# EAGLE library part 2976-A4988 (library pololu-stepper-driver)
A4988 Stepper Motor Driver Carrier; Black Edition (Bulk; No Header Pins) #2976 A4988 Stepper Motor Driver Carrier; Black Edition (Bulk; No Header Pins) in Japan, Suzaku Lab. Ltd. #2976 A4988 ステッピングモータドライバボード Black Edition (バルク品 ピンヘッダ無し)

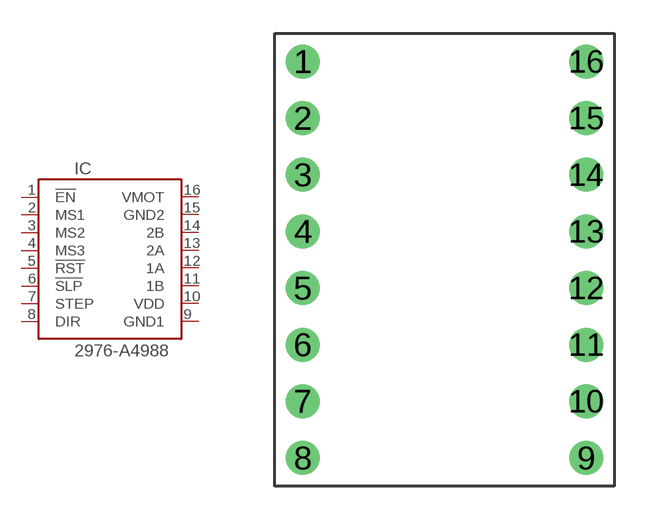
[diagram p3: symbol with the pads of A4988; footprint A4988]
Designator prefix IC

## 2976-A4988  [A4988]
1  !EN  pas
2  MS1  pas
3  MS2  pas
4  MS3  pas
5  !RST  pas
6  !SLP  pas
7  STEP  in
8  DIR  in
9  GND1  pwr
10  VDD  pwr
11  1B  out
12  1A  out
13  2A  out
14  2B  out
15  GND2  pwr
16  VMOT  pwr

## Footprint A4988 (pad centres in mm)
A4988 Stepper Motor Driver Carriers
drill 1.016: 1 -6.35,8.89; 2 -6.35,6.35; 3 -6.35,3.81; 4 -6.35,1.27; 5 -6.35,-1.27; 6 -6.35,-3.81; 7 -6.35,-6.35; 8 -6.35,-8.89; 9 6.35,-8.89; 10 6.35,-6.35; 11 6.35,-3.81; 12 6.35,-1.27; 13 6.35,1.27; 14 6.35,3.81; 15 6.35,6.35; 16 6.35,8.89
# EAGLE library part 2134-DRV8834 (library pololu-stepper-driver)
DRV8834 Low-Voltage Stepper Motor Driver Carrier #2134 DRV8834 Low-Voltage Stepper Motor Driver Carrier in Japan, Suzaku Lab. Ltd. #2134 DRV8834 低電圧用ステッピングモータドライバ

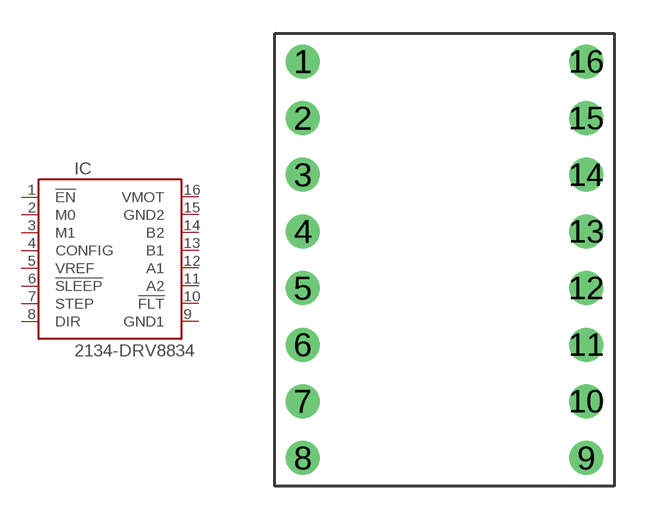
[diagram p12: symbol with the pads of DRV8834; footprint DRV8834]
Designator prefix IC

## 2134-DRV8834  [DRV8834]
1  !EN  pas
2  M0  pas
3  M1  pas
4  CONFIG  pas
5  VREF  pas
6  !SLEEP  in
7  STEP  in
8  DIR  in
9  GND1  pwr
10  !FLT  oc
11  A2  out
12  A1  out
13  B1  out
14  B2  out
15  GND2  pwr
16  VMOT  pwr

## Footprint DRV8834 (pad centres in mm)
DRV8834 Low-Voltage Stepper Motor Driver
drill 1.016: 1 -6.35,8.89; 2 -6.35,6.35; 3 -6.35,3.81; 4 -6.35,1.27; 5 -6.35,-1.27; 6 -6.35,-3.81; 7 -6.35,-6.35; 8 -6.35,-8.89; 9 6.35,-8.89; 10 6.35,-6.35; 11 6.35,-3.81; 12 6.35,-1.27; 13 6.35,1.27; 14 6.35,3.81; 15 6.35,6.35; 16 6.35,8.89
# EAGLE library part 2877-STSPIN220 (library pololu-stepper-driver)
STSPIN220 Low-Voltage Stepper Motor Driver Carrier (Header Pins Soldered) #2877 STSPIN220 Low-Voltage Stepper Motor Driver Carrier (Header Pins Soldered) in Japan, Suzaku Lab. Ltd. #2877 STSPIN220ステッピングモータードライバボード（ハンダ付済み）

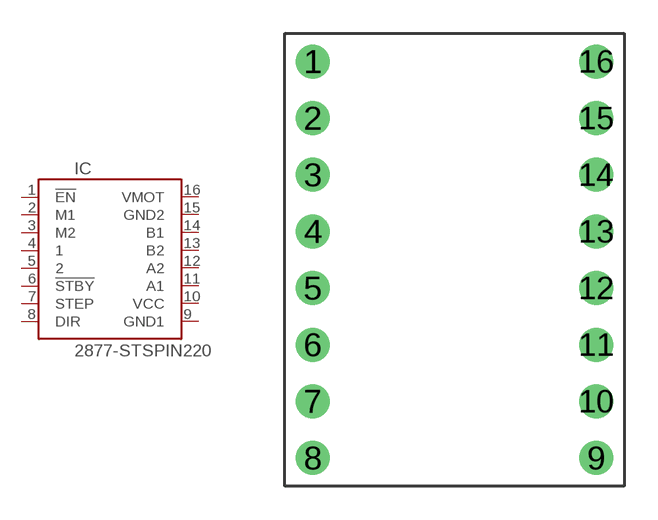
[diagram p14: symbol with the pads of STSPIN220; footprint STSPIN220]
Designator prefix IC

## 2877-STSPIN220  [STSPIN220]
1  !EN  pas
2  M1  in
3  M2  in
4  1  pas
5  2  pas
6  !STBY  pas
7  STEP  in
8  DIR  in
9  GND1  pwr
10  VCC  pwr
11  A1  out
12  A2  out
13  B2  out
14  B1  out
15  GND2  pwr
16  VMOT  pwr

## Footprint STSPIN220 (pad centres in mm)
STSPIN220 Low-Voltage Stepper Motor Driver
drill 1.016: 1 -6.35,8.89; 2 -6.35,6.35; 3 -6.35,3.81; 4 -6.35,1.27; 5 -6.35,-1.27; 6 -6.35,-3.81; 7 -6.35,-6.35; 8 -6.35,-8.89; 9 6.35,-8.89; 10 6.35,-6.35; 11 6.35,-3.81; 12 6.35,-1.27; 13 6.35,1.27; 14 6.35,3.81; 15 6.35,6.35; 16 6.35,8.89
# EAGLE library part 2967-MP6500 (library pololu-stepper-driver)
MP6500 Stepper Motor Driver Carrier; Potentiometer Current Control (Header Pins Soldered) #2967 MP6500 Stepper Motor Driver Carrier; Potentiometer Current Control (Header Pins Soldered) in Japan, Suzaku Lab. Ltd. #2967 MP6500ステッピングモータドライバボード ポテンショメータ式電流制御 (ヘッダーピン実装済み)

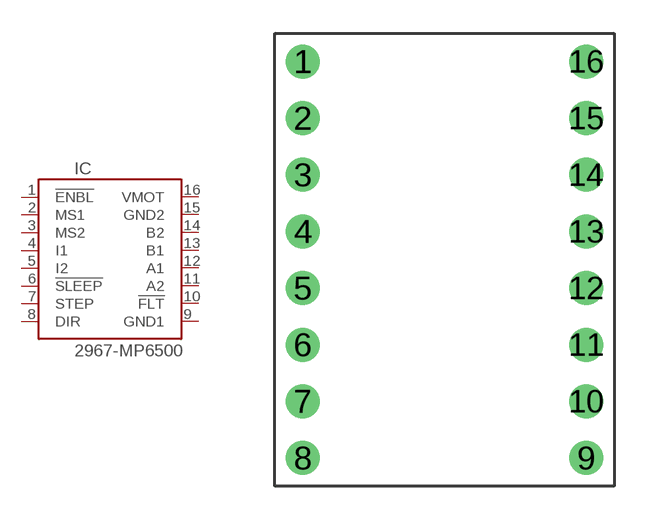
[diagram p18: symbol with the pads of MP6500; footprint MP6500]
Designator prefix IC

## 2967-MP6500  [MP6500]
1  !ENBL  pas
2  MS1  pas
3  MS2  pas
4  I1  pas
5  I2  pas
6  !SLEEP  in
7  STEP  in
8  DIR  in
9  GND1  pwr
10  !FLT  oc
11  A2  out
12  A1  out
13  B1  out
14  B2  out
15  GND2  pwr
16  VMOT  pwr

## Footprint MP6500 (pad centres in mm)
MP6500 Stepper Motor Driver
drill 1.016: 1 -6.35,8.89; 2 -6.35,6.35; 3 -6.35,3.81; 4 -6.35,1.27; 5 -6.35,-1.27; 6 -6.35,-3.81; 7 -6.35,-6.35; 8 -6.35,-8.89; 9 6.35,-8.89; 10 6.35,-6.35; 11 6.35,-3.81; 12 6.35,-1.27; 13 6.35,1.27; 14 6.35,3.81; 15 6.35,6.35; 16 6.35,8.89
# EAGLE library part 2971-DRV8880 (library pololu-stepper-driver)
DRV8880 Stepper Motor Driver Carrier #2971 DRV8880 Stepper Motor Driver Carrier in Japan, Suzaku Lab. Ltd. #2971 DRV8880ステッピングモータドライバボード

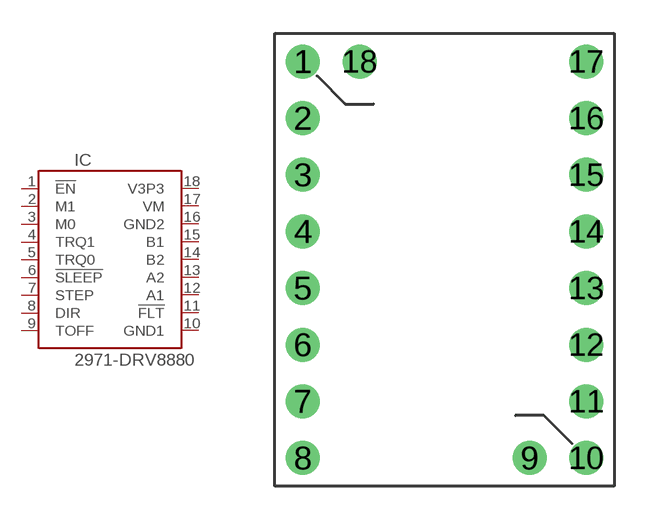
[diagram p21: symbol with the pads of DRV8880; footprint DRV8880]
Designator prefix IC

## 2971-DRV8880  [DRV8880]
1  !EN  pas
2  M1  pas
3  M0  pas
4  TRQ1  pas
5  TRQ0  pas
6  !SLEEP  in
7  STEP  in
8  DIR  in
9  TOFF  pas
10  GND1  pwr
11  !FLT  oc
12  A1  out
13  A2  out
14  B2  out
15  B1  out
16  GND2  pwr
17  VM  pwr
18  V3P3  sup

## Footprint DRV8880 (pad centres in mm)
DRV8880 Stepper Motor Driver
drill 1.016: 1 -6.35,8.89; 2 -6.35,6.35; 3 -6.35,3.81; 4 -6.35,1.27; 5 -6.35,-1.27; 6 -6.35,-3.81; 7 -6.35,-6.35; 8 -6.35,-8.89; 9 3.81,-8.89; 10 6.35,-8.89; 11 6.35,-6.35; 12 6.35,-3.81; 13 6.35,-1.27; 14 6.35,1.27; 15 6.35,3.81; 16 6.35,6.35; 17 6.35,8.89; 18 -3.81,8.89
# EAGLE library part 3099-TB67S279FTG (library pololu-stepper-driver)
TB67S279FTG Stepper Motor Driver Compact Carrier (Header Pins Soldered) #3099 TB67S279FTG Stepper Motor Driver Compact Carrier (Header Pins Soldered) in Japan, Suzaku Lab. Ltd. #3099 TB67S279FTGステッピングモータードライバコンパクトボード （ヘッダーピン実装済み）

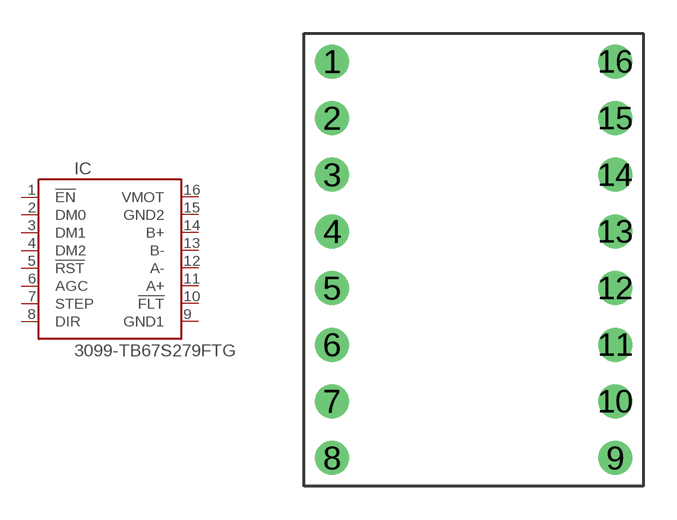
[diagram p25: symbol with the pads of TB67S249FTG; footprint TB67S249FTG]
Designator prefix IC

## 3099-TB67S279FTG  [TB67S249FTG]
1  !EN  pas
2  DM0  in
3  DM1  in
4  DM2  in
5  !RST  pas
6  AGC  pas
7  STEP  in
8  DIR  in
9  GND1  pwr
10  !FLT  oc
11  A+  out
12  A-  out
13  B-  out
14  B+  out
15  GND2  pwr
16  VMOT  pwr

## Footprint TB67S249FTG (pad centres in mm)
TB67S249FTG Stepper Motor Driver
drill 1.016: 1 -6.35,8.89; 2 -6.35,6.35; 3 -6.35,3.81; 4 -6.35,1.27; 5 -6.35,-1.27; 6 -6.35,-3.81; 7 -6.35,-6.35; 8 -6.35,-8.89; 9 6.35,-8.89; 10 6.35,-6.35; 11 6.35,-3.81; 12 6.35,-1.27; 13 6.35,1.27; 14 6.35,3.81; 15 6.35,6.35; 16 6.35,8.89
